VERSION 5.7 ;
  NOWIREEXTENSIONATPIN ON ;
  DIVIDERCHAR "/" ;
  BUSBITCHARS "[]" ;
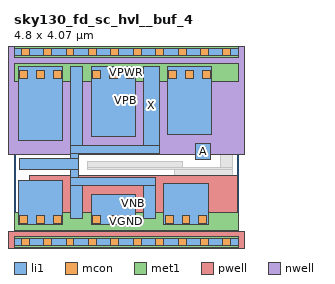
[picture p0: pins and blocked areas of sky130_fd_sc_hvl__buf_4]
MACRO sky130_fd_sc_hvl__buf_4
  CLASS BLOCK ;
  FOREIGN sky130_fd_sc_hvl__buf_4 ;
  ORIGIN 0.000 0.000 ;
  SIZE 4.800 BY 4.070 ;
  PIN A
    ANTENNAGATEAREA 1.125000 ;
    PORT
      LAYER li1 ;
        RECT 3.885 1.775 4.215 2.120 ;
    END
  END A
  PIN VGND
    USE GROUND ;
    PORT
      LAYER li1 ;
        RECT 0.090 0.365 1.040 1.325 ;
        RECT 1.650 0.365 2.600 1.025 ;
        RECT 3.210 0.365 4.160 1.245 ;
      LAYER mcon ;
        RECT 0.120 0.395 0.290 0.565 ;
        RECT 0.480 0.395 0.650 0.565 ;
        RECT 0.840 0.395 1.010 0.565 ;
        RECT 1.680 0.395 1.850 0.565 ;
        RECT 2.040 0.395 2.210 0.565 ;
        RECT 2.400 0.395 2.570 0.565 ;
        RECT 3.240 0.395 3.410 0.565 ;
        RECT 3.600 0.395 3.770 0.565 ;
        RECT 3.960 0.395 4.130 0.565 ;
      LAYER met1 ;
        RECT 0.000 0.255 4.800 0.625 ;
    END
  END VGND
  PIN VNB
    ANTENNADIFFAREA 0.816000 ;
    PORT
      LAYER pwell ;
        RECT 0.330 0.215 4.780 1.415 ;
        RECT -0.130 -0.215 4.930 0.215 ;
      LAYER li1 ;
        RECT 0.000 -0.085 4.800 0.085 ;
      LAYER mcon ;
        RECT 0.155 -0.085 0.325 0.085 ;
        RECT 0.635 -0.085 0.805 0.085 ;
        RECT 1.115 -0.085 1.285 0.085 ;
        RECT 1.595 -0.085 1.765 0.085 ;
        RECT 2.075 -0.085 2.245 0.085 ;
        RECT 2.555 -0.085 2.725 0.085 ;
        RECT 3.035 -0.085 3.205 0.085 ;
        RECT 3.515 -0.085 3.685 0.085 ;
        RECT 3.995 -0.085 4.165 0.085 ;
        RECT 4.475 -0.085 4.645 0.085 ;
      LAYER met1 ;
        RECT 0.000 -0.115 4.800 0.115 ;
    END
  END VNB
  PIN VPB
    ANTENNADIFFAREA 0.816000 ;
    PORT
      LAYER nwell ;
        RECT -0.330 1.885 5.130 4.485 ;
      LAYER li1 ;
        RECT 0.000 3.985 4.800 4.155 ;
      LAYER mcon ;
        RECT 0.155 3.985 0.325 4.155 ;
        RECT 0.635 3.985 0.805 4.155 ;
        RECT 1.115 3.985 1.285 4.155 ;
        RECT 1.595 3.985 1.765 4.155 ;
        RECT 2.075 3.985 2.245 4.155 ;
        RECT 2.555 3.985 2.725 4.155 ;
        RECT 3.035 3.985 3.205 4.155 ;
        RECT 3.515 3.985 3.685 4.155 ;
        RECT 3.995 3.985 4.165 4.155 ;
        RECT 4.475 3.985 4.645 4.155 ;
      LAYER met1 ;
        RECT 0.000 3.955 4.800 4.185 ;
    END
  END VPB
  PIN VPWR
    USE POWER ;
    PORT
      LAYER li1 ;
        RECT 0.090 2.175 1.040 3.755 ;
        RECT 1.650 2.255 2.600 3.755 ;
        RECT 3.290 2.300 4.240 3.755 ;
      LAYER mcon ;
        RECT 0.120 3.505 0.290 3.675 ;
        RECT 0.480 3.505 0.650 3.675 ;
        RECT 0.840 3.505 1.010 3.675 ;
        RECT 1.680 3.505 1.850 3.675 ;
        RECT 2.040 3.505 2.210 3.675 ;
        RECT 2.400 3.505 2.570 3.675 ;
        RECT 3.320 3.505 3.490 3.675 ;
        RECT 3.680 3.505 3.850 3.675 ;
        RECT 4.040 3.505 4.210 3.675 ;
      LAYER met1 ;
        RECT 0.000 3.445 4.800 3.815 ;
    END
  END VPWR
  PIN X
    ANTENNADIFFAREA 1.260000 ;
    PORT
      LAYER li1 ;
        RECT 1.220 2.075 1.470 3.755 ;
        RECT 2.780 2.075 3.110 3.755 ;
        RECT 1.220 1.905 3.110 2.075 ;
        RECT 1.220 1.780 1.390 1.905 ;
        RECT 0.125 1.550 1.390 1.780 ;
        RECT 1.220 1.375 1.390 1.550 ;
        RECT 1.220 1.205 3.030 1.375 ;
        RECT 1.220 0.495 1.470 1.205 ;
        RECT 2.780 0.495 3.030 1.205 ;
    END
  END X
  OBS
      LAYER li1 ;
        RECT 1.570 1.595 3.600 1.725 ;
        RECT 4.420 1.595 4.670 3.755 ;
        RECT 1.570 1.555 4.670 1.595 ;
        RECT 3.430 1.425 4.670 1.555 ;
        RECT 4.340 0.495 4.670 1.425 ;
  END
END sky130_fd_sc_hvl__buf_4
END LIBRARY

